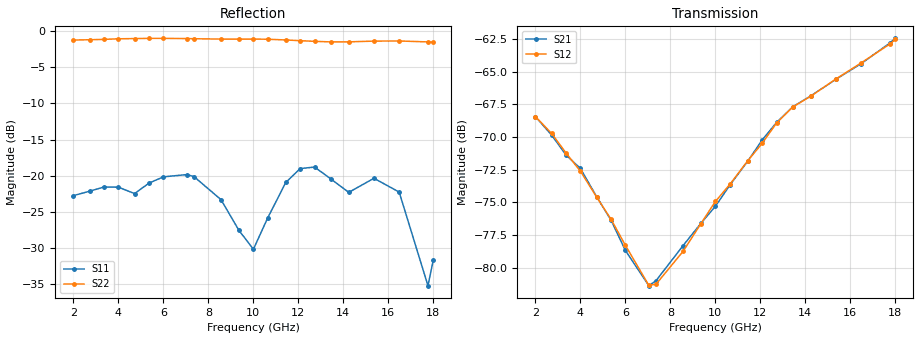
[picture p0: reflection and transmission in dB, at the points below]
!Keysight Technologies,P5004A,MY58100454,A.15.10.06
!Date: Monday, July 18, 2022 10:36:05
!Correction: S11(C  2-Port  )
!S21(C  2-Port  )
!S12(C  2-Port  )
!S22(C  2-Port  )
!S2P File: Measurements: S11, S21, S12, S22:
# Hz S  dB  R 50
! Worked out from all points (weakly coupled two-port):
!   201 points, 2 GHz to 18 GHz, reference 50 ohm
!   highest |S21| = -62.45 dB at 18 GHz (marker M1); lowest = -81.4 dB at 7.04 GHz (marker M2)
!   lowest |S11| = -35.2 dB at 17.76 GHz (marker M3), VSWR 1.04, Z = 48.5 + j0.74 ohm
!   |S11| at or under -10 dB: start of sweep to end of sweep
!   |S22| runs from -1.5 to -1.0 dB; largest |S21 - S12| = 1.9e-05
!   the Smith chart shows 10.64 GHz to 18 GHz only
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2e9  -22.74 -73.4  -68.44 -103.8  -68.44 -103.5  -1.27 72.0
2.72e9  -22.13 -112.5  -69.86 -150.8  -69.73 -150.7  -1.23 31.4
3.36e9  -21.55 -136.9  -71.38 173.4  -71.23 173.2  -1.18 -4.2
4e9  -21.58 -176.8  -72.41 139.4  -72.62 138.8  -1.10 -39.8
4.72e9  -22.46 156.8  -74.57 103.0  -74.60 101.6  -1.07 -80.0
5.36e9  -21.01 124.6  -76.37 72.4  -76.30 72.7  -1.04 -115.7
6e9  -20.15 86.5  -78.69 49.3  -78.30 48.2  -1.04 -151.5
7.04e9  -19.84 15.9  -81.39 24.7  -81.36 23.5  -1.07 150.8
7.36e9  -20.12 -8.0  -81.01 19.5  -81.28 18.6  -1.09 133.3
8.56e9  -23.30 -99.0  -78.33 -9.4  -78.77 -8.8  -1.14 69.1
9.36e9  -27.55 -151.3  -76.61 -35.9  -76.63 -37.6  -1.14 27.8
1e10  -30.14 -159.4  -75.31 -64.9  -74.94 -65.2  -1.14 -5.1
1.064e10  -25.79 -172.7  -73.70 -92.3  -73.64 -92.6  -1.16 -38.3
1.144e10  -20.92 137.8  -71.85 -126.8  -71.82 -126.2  -1.26 -80.6
1.208e10  -19.01 94.7  -70.23 -158.4  -70.49 -157.7  -1.36 -115.4
1.272e10  -18.80 54.3  -68.89 168.4  -68.93 169.1  -1.45 -151.1
1.344e10  -20.43 18.7  -67.69 129.6  -67.71 129.0  -1.53 167.8
1.424e10  -22.29 3.4  -66.86 87.5  -66.88 87.0  -1.52 121.8
1.536e10  -20.35 -26.7  -65.58 29.9  -65.56 29.8  -1.42 58.4
1.648e10  -22.25 -79.3  -64.39 -26.7  -64.33 -26.1  -1.40 -1.9
1.776e10  -35.17 154.0  -62.80 -93.1  -62.88 -92.8  -1.53 -67.3
1.8e10  -31.59 94.2  -62.45 -105.5  -62.52 -104.9  -1.54 -79.3
